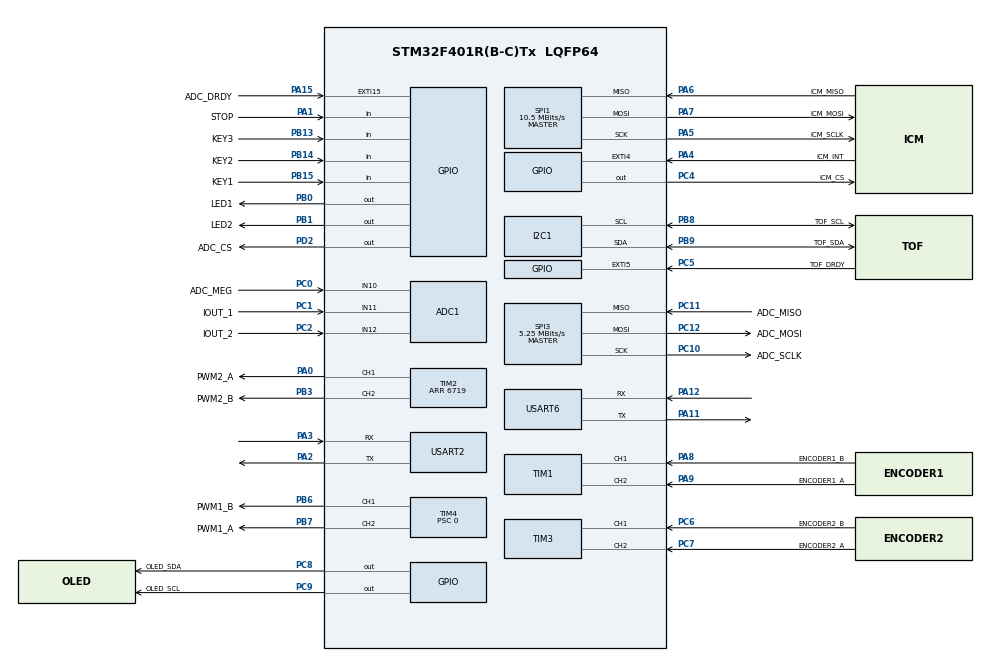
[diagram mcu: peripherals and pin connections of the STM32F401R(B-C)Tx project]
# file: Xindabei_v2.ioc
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ADC1.Channel-0\#ChannelRegularConversion=ADC_CHANNEL_10
ADC1.Channel-3\#ChannelInjectedConversion=ADC_CHANNEL_11
ADC1.Channel-4\#ChannelInjectedConversion=ADC_CHANNEL_12
ADC1.ExternalTrigConv=ADC_SOFTWARE_START
ADC1.ExternalTrigInjecConv=ADC_INJECTED_SOFTWARE_START
ADC1.InjNumberOfConversion=2
ADC1.InjectedOffset-3\#ChannelInjectedConversion=0
ADC1.InjectedOffset-4\#ChannelInjectedConversion=0
ADC1.InjectedRank-3\#ChannelInjectedConversion=1
ADC1.InjectedRank-4\#ChannelInjectedConversion=2
ADC1.NbrOfConversion=1
ADC1.NbrOfConversionFlag=1
ADC1.Rank-0\#ChannelRegularConversion=1
ADC1.SamplingTime-0\#ChannelRegularConversion=ADC_SAMPLETIME_480CYCLES
ADC1.SamplingTime-3\#ChannelInjectedConversion=ADC_SAMPLETIME_56CYCLES
ADC1.SamplingTime-4\#ChannelInjectedConversion=ADC_SAMPLETIME_56CYCLES
ADC1.master=1
Dma.ADC1.3.Direction=DMA_PERIPH_TO_MEMORY
Dma.ADC1.3.FIFOMode=DMA_FIFOMODE_DISABLE
Dma.ADC1.3.Instance=DMA2_Stream0
Dma.ADC1.3.MemDataAlignment=DMA_MDATAALIGN_HALFWORD
Dma.ADC1.3.MemInc=DMA_MINC_ENABLE
Dma.ADC1.3.Mode=DMA_CIRCULAR
Dma.ADC1.3.PeriphDataAlignment=DMA_PDATAALIGN_HALFWORD
Dma.ADC1.3.PeriphInc=DMA_PINC_DISABLE
Dma.ADC1.3.Priority=DMA_PRIORITY_LOW
Dma.Request0=USART2_RX
Dma.Request1=USART2_TX
Dma.Request2=SPI1_TX
Dma.Request3=ADC1
Dma.Request4=USART6_RX
Dma.Request5=USART6_TX
Dma.SPI1_TX.2.Direction=DMA_MEMORY_TO_PERIPH
Dma.SPI1_TX.2.FIFOMode=DMA_FIFOMODE_DISABLE
Dma.SPI1_TX.2.Instance=DMA2_Stream3
Dma.SPI1_TX.2.MemDataAlignment=DMA_MDATAALIGN_BYTE
Dma.SPI1_TX.2.MemInc=DMA_MINC_ENABLE
Dma.SPI1_TX.2.Mode=DMA_NORMAL
Dma.SPI1_TX.2.PeriphDataAlignment=DMA_PDATAALIGN_BYTE
Dma.SPI1_TX.2.PeriphInc=DMA_PINC_DISABLE
Dma.SPI1_TX.2.Priority=DMA_PRIORITY_LOW
Dma.USART2_RX.0.Direction=DMA_PERIPH_TO_MEMORY
Dma.USART2_RX.0.FIFOMode=DMA_FIFOMODE_DISABLE
Dma.USART2_RX.0.Instance=DMA1_Stream5
Dma.USART2_RX.0.MemDataAlignment=DMA_MDATAALIGN_BYTE
Dma.USART2_RX.0.MemInc=DMA_MINC_ENABLE
Dma.USART2_RX.0.Mode=DMA_NORMAL
Dma.USART2_RX.0.PeriphDataAlignment=DMA_PDATAALIGN_BYTE
Dma.USART2_RX.0.PeriphInc=DMA_PINC_DISABLE
Dma.USART2_RX.0.Priority=DMA_PRIORITY_LOW
Dma.USART2_TX.1.Direction=DMA_MEMORY_TO_PERIPH
Dma.USART2_TX.1.FIFOMode=DMA_FIFOMODE_DISABLE
Dma.USART2_TX.1.Instance=DMA1_Stream6
Dma.USART2_TX.1.MemDataAlignment=DMA_MDATAALIGN_BYTE
Dma.USART2_TX.1.MemInc=DMA_MINC_ENABLE
Dma.USART2_TX.1.Mode=DMA_NORMAL
Dma.USART2_TX.1.PeriphDataAlignment=DMA_PDATAALIGN_BYTE
Dma.USART2_TX.1.PeriphInc=DMA_PINC_DISABLE
Dma.USART2_TX.1.Priority=DMA_PRIORITY_LOW
Dma.USART6_RX.4.Direction=DMA_PERIPH_TO_MEMORY
Dma.USART6_RX.4.FIFOMode=DMA_FIFOMODE_DISABLE
Dma.USART6_RX.4.Instance=DMA2_Stream1
Dma.USART6_RX.4.MemDataAlignment=DMA_MDATAALIGN_BYTE
Dma.USART6_RX.4.MemInc=DMA_MINC_ENABLE
Dma.USART6_RX.4.Mode=DMA_NORMAL
Dma.USART6_RX.4.PeriphDataAlignment=DMA_PDATAALIGN_BYTE
Dma.USART6_RX.4.PeriphInc=DMA_PINC_DISABLE
Dma.USART6_RX.4.Priority=DMA_PRIORITY_LOW
Dma.USART6_TX.5.Direction=DMA_MEMORY_TO_PERIPH
Dma.USART6_TX.5.FIFOMode=DMA_FIFOMODE_DISABLE
Dma.USART6_TX.5.Instance=DMA2_Stream6
Dma.USART6_TX.5.MemDataAlignment=DMA_MDATAALIGN_BYTE
Dma.USART6_TX.5.MemInc=DMA_MINC_ENABLE
Dma.USART6_TX.5.Mode=DMA_NORMAL
Dma.USART6_TX.5.PeriphDataAlignment=DMA_PDATAALIGN_BYTE
Dma.USART6_TX.5.PeriphInc=DMA_PINC_DISABLE
Dma.USART6_TX.5.Priority=DMA_PRIORITY_LOW
FREERTOS.Queues01=uartQueue,128,uint16_t,0,Dynamic,NULL,NULL
FREERTOS.Tasks01=defaultTask,21,386,StartDefaultTask,Default,NULL,Dynamic,NULL,NULL;ToFCapture,15,512,TofTask,Default,NULL,Dynamic,NULL,NULL;UartTask,8,512,UartTaskFunc,Default,NULL,Dynamic,NULL,NULL;MotorSpeedTask,48,256,MotorSpeedTaskFunc,Default,NULL,Dynamic,NULL,NULL;AdcCapture,48,512,AdcCaptureFunc,Default,NULL,Dynamic,NULL,NULL;CarControlTask,32,256,CarControlTaskFunc,Default,NULL,Dynamic,NULL,NULL;GyroTask,25,256,GyroTaskFunc,Default,NULL,Dynamic,NULL,NULL;TrackTask,28,256,TrackTaskFunc,Default,NULL,Dynamic,NULL,NULL
FREERTOS.configENABLE_FPU=1
I2C1.I2C_Mode=I2C_Fast
Mcu.Family=STM32F4
Mcu.Name=STM32F401R(B-C)Tx
Mcu.Package=LQFP64
NVIC.DMA1_Stream5_IRQn=true\:5\:0\:false\:false\:true\:true\:false\:true\:true
NVIC.DMA1_Stream6_IRQn=true\:5\:0\:false\:false\:true\:true\:false\:true\:true
NVIC.DMA2_Stream0_IRQn=true\:5\:0\:false\:false\:true\:false\:false\:true\:true
NVIC.DMA2_Stream1_IRQn=true\:5\:0\:false\:false\:true\:true\:false\:true\:true
NVIC.DMA2_Stream3_IRQn=true\:5\:0\:false\:false\:true\:true\:false\:true\:true
NVIC.DMA2_Stream6_IRQn=true\:5\:0\:false\:false\:true\:true\:false\:true\:true
NVIC.EXTI15_10_IRQn=true\:5\:0\:false\:false\:true\:true\:true\:true\:true
NVIC.EXTI4_IRQn=true\:5\:0\:false\:false\:true\:true\:true\:true\:true
NVIC.EXTI9_5_IRQn=true\:5\:0\:false\:false\:true\:true\:true\:true\:true
NVIC.PriorityGroup=NVIC_PRIORITYGROUP_4
NVIC.TIM1_TRG_COM_TIM11_IRQn=true\:15\:0\:false\:false\:true\:false\:false\:true\:true
NVIC.TimeBase=TIM1_TRG_COM_TIM11_IRQn
NVIC.TimeBaseIP=TIM11
NVIC.USART2_IRQn=true\:5\:0\:false\:false\:true\:true\:true\:true\:true
NVIC.USART6_IRQn=true\:5\:0\:false\:false\:true\:true\:true\:true\:true
PA0-WKUP.GPIO_Label=PWM2_A
PA0-WKUP.Signal=S_TIM2_CH1_ETR
PA1.GPIO_Label=STOP
PA1.GPIO_PuPd=GPIO_PULLUP
PA1.Signal=GPIO_Input
PA11.Mode=Asynchronous
PA11.Signal=USART6_TX
PA12.Mode=Asynchronous
PA12.Signal=USART6_RX
PA13.Mode=Serial_Wire
PA13.Signal=SYS_JTMS-SWDIO
PA14.Mode=Serial_Wire
PA14.Signal=SYS_JTCK-SWCLK
PA15.GPIO_Label=ADC_DRDY
PA15.GPIO_ModeDefaultEXTI=GPIO_MODE_IT_FALLING
PA15.GPIO_PuPd=GPIO_PULLUP
PA15.Signal=GPXTI15
PA2.GPIO_PuPd=GPIO_PULLUP
PA2.Mode=Asynchronous
PA2.Signal=USART2_TX
PA3.GPIO_PuPd=GPIO_PULLUP
PA3.Mode=Asynchronous
PA3.Signal=USART2_RX
PA4.GPIO_Label=ICM_INT
PA4.GPIO_PuPd=GPIO_PULLUP
PA4.Signal=GPXTI4
PA5.GPIO_Label=ICM_SCLK
PA5.Mode=Full_Duplex_Master
PA5.Signal=SPI1_SCK
PA6.GPIO_Label=ICM_MISO
PA6.Mode=Full_Duplex_Master
PA6.Signal=SPI1_MISO
PA7.GPIO_Label=ICM_MOSI
PA7.Mode=Full_Duplex_Master
PA7.Signal=SPI1_MOSI
PA8.GPIO_Label=ENCODER1_B
PA8.GPIO_PuPd=GPIO_PULLUP
PA8.Signal=S_TIM1_CH1
PA9.GPIO_Label=ENCODER1_A
PA9.GPIO_ModeDefaultPP=GPIO_MODE_AF_PP
PA9.GPIO_PuPd=GPIO_PULLUP
PA9.Signal=S_TIM1_CH2
PB0.GPIO_Label=LED1
PB0.Signal=GPIO_Output
PB1.GPIO_Label=LED2
PB1.Signal=GPIO_Output
PB13.GPIO_Label=KEY3
PB13.GPIO_PuPd=GPIO_PULLUP
PB13.Signal=GPIO_Input
PB14.GPIO_Label=KEY2
PB14.GPIO_PuPd=GPIO_PULLUP
PB14.Signal=GPIO_Input
PB15.GPIO_Label=KEY1
PB15.GPIO_PuPd=GPIO_PULLUP
PB15.Signal=GPIO_Input
PB3.GPIO_Label=PWM2_B
PB3.Signal=S_TIM2_CH2
PB6.GPIO_Label=PWM1_B
PB6.Signal=S_TIM4_CH1
PB7.GPIO_Label=PWM1_A
PB7.Signal=S_TIM4_CH2
PB8.GPIO_Label=TOF_SCL
PB8.Mode=I2C
PB8.Signal=I2C1_SCL
PB9.GPIO_Label=TOF_SDA
PB9.Mode=I2C
PB9.Signal=I2C1_SDA
PC0.GPIO_Label=ADC_MEG
PC0.Signal=ADCx_IN10
PC1.GPIO_Label=IOUT_1
PC1.Signal=ADCx_IN11
PC10.GPIO_Label=ADC_SCLK
PC10.Mode=Full_Duplex_Master
PC10.Signal=SPI3_SCK
PC11.GPIO_Label=ADC_MISO
PC11.Mode=Full_Duplex_Master
PC11.Signal=SPI3_MISO
PC12.GPIO_Label=ADC_MOSI
PC12.Mode=Full_Duplex_Master
PC12.Signal=SPI3_MOSI
PC2.GPIO_Label=IOUT_2
PC2.Signal=ADCx_IN12
PC4.GPIO_Label=ICM_CS
PC4.GPIO_PuPd=GPIO_NOPULL
PC4.GPIO_Speed=GPIO_SPEED_FREQ_VERY_HIGH
PC4.PinState=GPIO_PIN_SET
PC4.Signal=GPIO_Output
PC5.GPIO_Label=TOF_DRDY
PC5.GPIO_ModeDefaultEXTI=GPIO_MODE_IT_FALLING
PC5.Signal=GPXTI5
PC6.GPIO_Label=ENCODER2_B
PC6.GPIO_PuPd=GPIO_PULLUP
PC6.Signal=S_TIM3_CH1
PC7.GPIO_Label=ENCODER2_A
PC7.GPIO_PuPd=GPIO_PULLUP
PC7.Signal=S_TIM3_CH2
PC8.GPIO_Label=OLED_SDA
PC8.GPIO_ModeDefaultOutputPP=GPIO_MODE_OUTPUT_PP
PC8.GPIO_PuPd=GPIO_NOPULL
PC8.GPIO_Speed=GPIO_SPEED_FREQ_HIGH
PC8.PinState=GPIO_PIN_SET
PC8.Signal=GPIO_Output
PC9.GPIO_Label=OLED_SCL
PC9.GPIO_ModeDefaultOutputPP=GPIO_MODE_OUTPUT_PP
PC9.GPIO_PuPd=GPIO_NOPULL
PC9.GPIO_Speed=GPIO_SPEED_FREQ_HIGH
PC9.PinState=GPIO_PIN_SET
PC9.Signal=GPIO_Output
PD2.GPIO_Label=ADC_CS
PD2.GPIO_Speed=GPIO_SPEED_FREQ_VERY_HIGH
PD2.Signal=GPIO_Output
PH0\ -\ OSC_IN.Mode=HSE-External-Oscillator
PH0\ -\ OSC_IN.Signal=RCC_OSC_IN
PH1\ -\ OSC_OUT.Mode=HSE-External-Oscillator
PH1\ -\ OSC_OUT.Signal=RCC_OSC_OUT
ProjectManager.HeapSize=0x400
ProjectManager.StackSize=0x600
ProjectManager.TargetToolchain=CMake
RCC.48MHZClocksFreq_Value=42000000
RCC.AHBFreq_Value=84000000
RCC.APB1CLKDivider=RCC_HCLK_DIV2
RCC.APB1Freq_Value=42000000
RCC.APB1TimFreq_Value=84000000
RCC.APB2Freq_Value=84000000
RCC.APB2TimFreq_Value=84000000
RCC.CortexFreq_Value=84000000
RCC.HCLKFreq_Value=84000000
RCC.HSE_VALUE=16000000
RCC.HSI_VALUE=16000000
RCC.LSE_VALUE=32768
RCC.PLLM=8
RCC.PLLN=84
RCC.PLLSourceVirtual=RCC_PLLSOURCE_HSE
RCC.SYSCLKFreq_VALUE=84000000
RCC.SYSCLKSource=RCC_SYSCLKSOURCE_PLLCLK
RCC.VCOOutputFreq_Value=168000000
SH.ADCx_IN10.0=ADC1_IN10,IN10
SH.ADCx_IN11.0=ADC1_IN11,IN11
SH.ADCx_IN12.0=ADC1_IN12,IN12
SH.S_TIM1_CH1.0=TIM1_CH1,Encoder_Interface
SH.S_TIM1_CH2.0=TIM1_CH2,Encoder_Interface
SH.S_TIM2_CH1_ETR.0=TIM2_CH1,PWM Generation1 CH1
SH.S_TIM2_CH2.0=TIM2_CH2,PWM Generation2 CH2
SH.S_TIM3_CH1.0=TIM3_CH1,Encoder_Interface
SH.S_TIM3_CH2.0=TIM3_CH2,Encoder_Interface
SH.S_TIM4_CH1.0=TIM4_CH1,PWM Generation1 CH1
SH.S_TIM4_CH2.0=TIM4_CH2,PWM Generation2 CH2
SPI1.BaudRatePrescaler=SPI_BAUDRATEPRESCALER_8
SPI1.CLKPhase=SPI_PHASE_2EDGE
SPI1.CLKPolarity=SPI_POLARITY_HIGH
SPI1.CalculateBaudRate=10.5 MBits/s
SPI1.Direction=SPI_DIRECTION_2LINES
SPI1.Mode=SPI_MODE_MASTER
SPI1.VirtualType=VM_MASTER
SPI3.BaudRatePrescaler=SPI_BAUDRATEPRESCALER_8
SPI3.CLKPhase=SPI_PHASE_2EDGE
SPI3.CalculateBaudRate=5.25 MBits/s
SPI3.Direction=SPI_DIRECTION_2LINES
SPI3.Mode=SPI_MODE_MASTER
SPI3.VirtualType=VM_MASTER
TIM1.EncoderMode=TIM_ENCODERMODE_TI12
TIM1.IC1Filter=5
TIM1.IC1Polarity=TIM_ICPOLARITY_FALLING
TIM1.IC2Filter=5
TIM1.IC2Polarity=TIM_ICPOLARITY_FALLING
TIM2.Channel-PWM\ Generation1\ CH1=TIM_CHANNEL_1
TIM2.Channel-PWM\ Generation2\ CH2=TIM_CHANNEL_2
TIM2.Period=6719
TIM3.EncoderMode=TIM_ENCODERMODE_TI12
TIM3.IC1Filter=5
TIM3.IC1Polarity=TIM_ICPOLARITY_RISING
TIM3.IC2Filter=5
TIM3.IC2Polarity=TIM_ICPOLARITY_RISING
TIM4.AutoReloadPreload=TIM_AUTORELOAD_PRELOAD_ENABLE
TIM4.Channel-PWM\ Generation1\ CH1=TIM_CHANNEL_1
TIM4.Channel-PWM\ Generation2\ CH2=TIM_CHANNEL_2
TIM4.ClockDivision=TIM_CLOCKDIVISION_DIV1
TIM4.Period=6719
TIM4.Prescaler=0
TIM4.Pulse-PWM\ Generation1\ CH1=0
TIM5.Period=5000
TIM5.Prescaler=8
TIM5.TIM_MasterOutputTrigger=TIM_TRGO_UPDATE
TIM9.AutoReloadPreload=TIM_AUTORELOAD_PRELOAD_ENABLE
TIM9.ClockDivision=TIM_CLOCKDIVISION_DIV1
TIM9.Period=9550
TIM9.Prescaler=8
USART2.VirtualMode=VM_ASYNC
USART6.VirtualMode=VM_ASYNC
VP_FREERTOS_VS_CMSIS_V2.Mode=CMSIS_V2
VP_SYS_VS_tim11.Mode=TIM11
VP_TIM5_VS_ClockSourceINT.Mode=Internal
VP_TIM9_VS_ClockSourceINT.Mode=Internal
board=custom

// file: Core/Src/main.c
/* USER CODE BEGIN Header */
/**
 ******************************************************************************
 * @file           : main.c
 * @brief          : Main program body
 ******************************************************************************
 * @attention
 *
 * Copyright (c) 2025 STMicroelectronics.
 * All rights reserved.
 *
 * This software is licensed under terms that can be found in the LICENSE file
 * in the root directory of this software component.
 * If no LICENSE file comes with this software, it is provided AS-IS.
 *
 ******************************************************************************
 */
/*
                  _ooOoo_
                 o8888888o
                 88" . "88
                 (| -_- |)
                 O\ = /O
              ____/`---'\____
            .' \\| |// `
           / \\||| : |||// \
          / _||||| -:- |||||- \
          | | \\\ - /// | |
          | \_| ''\---/'' | |
          \ .-\__ `-` ___/-. /
        ___`. .' /--.--\ `. . __
     ."" '< `.___\_<|>_/___.' >'""
    | | : `- \`.;`\ _ /`;.`/ - ` : | |
    \ \ `-. \_ __\ /__ _/ .-` / /
======`-.____`-.___\_____/___.-`____.-'======
                  `=---='
^^^^^^^^^^^^^^^^^^^^^^^^^^^^^^^^^^^^^^^^^^^^^
           佛祖保佑 永无BUG
*/
/* USER CODE END Header */
#include "main.h"
#include "cmsis_os.h"
#include "adc.h"
#include "dma.h"
#include "i2c.h"
#include "spi.h"
#include "tim.h"
#include "usart.h"
#include "gpio.h"

/* USER CODE BEGIN Includes */
#include "motor.h"
/* USER CODE END Includes */

void SystemClock_Config(void);
void MX_FREERTOS_Init(void);

int main(void)
{

  /* MCU Configuration--------------------------------------------------------*/

  /* Reset of all peripherals, Initializes the Flash interface and the Systick. */
  HAL_Init();

  /* Configure the system clock */
  SystemClock_Config();

  /* Initialize all configured peripherals */
  MX_GPIO_Init();
  MX_DMA_Init();
  MX_TIM1_Init();
  MX_USART2_UART_Init();
  MX_SPI1_Init();
  MX_I2C1_Init();
  MX_ADC1_Init();
  MX_SPI3_Init();
  MX_TIM3_Init();
  MX_TIM4_Init();
  MX_TIM2_Init();
  MX_TIM9_Init();
  MX_TIM5_Init();
  MX_USART6_UART_Init();
  /* USER CODE BEGIN 2 */
  HAL_TIM_Base_Start_IT(&htim9); // 启动电流环定时器

  /* USER CODE END 2 */

  /* Init scheduler */
  osKernelInitialize();  /* Call init function for freertos objects (in cmsis_os2.c) */
  MX_FREERTOS_Init();

  /* Start scheduler */
  osKernelStart();

  /* We should never get here as control is now taken by the scheduler */

  /* Infinite loop */
  while (1) {

    /* USER CODE BEGIN 3 */
    HAL_GPIO_TogglePin(GPIOC, GPIO_PIN_13);
    osDelay(100);
  }
  /* USER CODE END 3 */
}

void SystemClock_Config(void)
{
  RCC_OscInitTypeDef RCC_OscInitStruct = {0};
  RCC_ClkInitTypeDef RCC_ClkInitStruct = {0};

  /** Configure the main internal regulator output voltage
  */
  __HAL_RCC_PWR_CLK_ENABLE();
  __HAL_PWR_VOLTAGESCALING_CONFIG(PWR_REGULATOR_VOLTAGE_SCALE1);  // Scale1 for higher frequency

  /** Initializes the RCC Oscillators according to the specified parameters
  * in the RCC_OscInitTypeDef structure.
  * OVERCLOCK: 96 MHz (official max is 84 MHz)
  * PLL_VCO = HSE / PLLM * PLLN = 16 / 8 * 96 = 192 MHz
  * SYSCLK = PLL_VCO / PLLP = 192 / 2 = 96 MHz
  */
  RCC_OscInitStruct.OscillatorType = RCC_OSCILLATORTYPE_HSE;
  RCC_OscInitStruct.HSEState = RCC_HSE_ON;
  RCC_OscInitStruct.PLL.PLLState = RCC_PLL_ON;
  RCC_OscInitStruct.PLL.PLLSource = RCC_PLLSOURCE_HSE;
  RCC_OscInitStruct.PLL.PLLM = 8;
  RCC_OscInitStruct.PLL.PLLN = 96;   // OVERCLOCK: 84 -> 96
  RCC_OscInitStruct.PLL.PLLP = RCC_PLLP_DIV2;
  RCC_OscInitStruct.PLL.PLLQ = 4;
  if (HAL_RCC_OscConfig(&RCC_OscInitStruct) != HAL_OK)
  {
    Error_Handler();
  }

  /** Initializes the CPU, AHB and APB buses clocks
  */
  RCC_ClkInitStruct.ClockType = RCC_CLOCKTYPE_HCLK|RCC_CLOCKTYPE_SYSCLK
                              |RCC_CLOCKTYPE_PCLK1|RCC_CLOCKTYPE_PCLK2;
  RCC_ClkInitStruct.SYSCLKSource = RCC_SYSCLKSOURCE_PLLCLK;
  RCC_ClkInitStruct.AHBCLKDivider = RCC_SYSCLK_DIV1;
  RCC_ClkInitStruct.APB1CLKDivider = RCC_HCLK_DIV2;
  RCC_ClkInitStruct.APB2CLKDivider = RCC_HCLK_DIV1;

  if (HAL_RCC_ClockConfig(&RCC_ClkInitStruct, FLASH_LATENCY_3) != HAL_OK)  // OVERCLOCK: 2 -> 3
  {
    Error_Handler();
  }
}

void HAL_TIM_PeriodElapsedCallback(TIM_HandleTypeDef *htim)
{
  /* USER CODE BEGIN Callback 0 */
  if (htim->Instance == TIM9) {
    // 电流环定时器
    CurrentLoopTimerHandler();
  }

  /* USER CODE END Callback 0 */
  if (htim->Instance == TIM11)
  {
    HAL_IncTick();
  }
}

void Error_Handler(void)
{
  __disable_irq();
  while (1) {
  }
}
#ifdef USE_FULL_ASSERT
/**
  * @brief  Reports the name of the source file and the source line number
  *         where the assert_param error has occurred.
  * @param  file: pointer to the source file name
  * @param  line: assert_param error line source number
  * @retval None
  */
void assert_failed(uint8_t *file, uint32_t line)
{
  /* USER CODE BEGIN 6 */
  /* User can add his own implementation to report the file name and line
     number, ex: printf("Wrong parameters value: file %s on line %d\r\n", file,
     line) */
  /* USER CODE END 6 */
}
#endif /* USE_FULL_ASSERT */

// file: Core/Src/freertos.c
/* USER CODE BEGIN Header */
/**
 ******************************************************************************
 * File Name          : freertos.c
 * Description        : Code for freertos applications
 ******************************************************************************
 * @attention
 *
 * Copyright (c) 2025 STMicroelectronics.
 * All rights reserved.
 *
 * This software is licensed under terms that can be found in the LICENSE file
 * in the root directory of this software component.
 * If no LICENSE file comes with this software, it is provided AS-IS.
 *
 ******************************************************************************
 */
/* USER CODE END Header */

#include "FreeRTOS.h"
#include "task.h"
#include "main.h"
#include "cmsis_os.h"

/* USER CODE BEGIN Includes */
#include "car_control.h"
#include "common.h"
#include "imu.h"
#include "meg_adc.h"
#include "motor.h"
#include "oled_service.h"
#include "param_server.h"
#include "tim.h"
#include "tof.h"
#include "track.h"
#include "uart_command.h"
#include "usart.h"
#include <stdint.h>
#include <stdio.h>
#include <string.h>

/* USER CODE END Includes */

/* USER CODE BEGIN Variables */
TaskHandle_t ToFMeasureTaskHandle;
TaskHandle_t AdcCaptureTaskHandle;
TaskHandle_t ImuCaptureTaskHandle;

/* USER CODE END Variables */
/* Definitions for defaultTask */
osThreadId_t defaultTaskHandle;
const osThreadAttr_t defaultTask_attributes = {
  .name = "defaultTask",
  .stack_size = 386 * 4,
  .priority = (osPriority_t) osPriorityBelowNormal5,
};
/* Definitions for ToFCapture */
osThreadId_t ToFCaptureHandle;
const osThreadAttr_t ToFCapture_attributes = {
  .name = "ToFCapture",
  .stack_size = 512 * 4,
  .priority = (osPriority_t) osPriorityLow7,
};
/* Definitions for UartTask */
osThreadId_t UartTaskHandle;
const osThreadAttr_t UartTask_attributes = {
  .name = "UartTask",
  .stack_size = 512 * 4,
  .priority = (osPriority_t) osPriorityLow,
};
/* Definitions for MotorSpeedTask */
osThreadId_t MotorSpeedTaskHandle;
const osThreadAttr_t MotorSpeedTask_attributes = {
  .name = "MotorSpeedTask",
  .stack_size = 256 * 4,
  .priority = (osPriority_t) osPriorityRealtime,
};
/* Definitions for AdcCapture */
osThreadId_t AdcCaptureHandle;
const osThreadAttr_t AdcCapture_attributes = {
  .name = "AdcCapture",
  .stack_size = 512 * 4,
  .priority = (osPriority_t) osPriorityRealtime,
};
/* Definitions for CarControlTask */
osThreadId_t CarControlTaskHandle;
const osThreadAttr_t CarControlTask_attributes = {
  .name = "CarControlTask",
  .stack_size = 256 * 4,
  .priority = (osPriority_t) osPriorityAboveNormal,
};
/* Definitions for GyroTask */
osThreadId_t GyroTaskHandle;
const osThreadAttr_t GyroTask_attributes = {
  .name = "GyroTask",
  .stack_size = 256 * 4,
  .priority = (osPriority_t) osPriorityNormal1,
};
/* Definitions for TrackTask */
osThreadId_t TrackTaskHandle;
const osThreadAttr_t TrackTask_attributes = {
  .name = "TrackTask",
  .stack_size = 256 * 4,
  .priority = (osPriority_t) osPriorityNormal4,
};
/* Definitions for uartQueue */
osMessageQueueId_t uartQueueHandle;
const osMessageQueueAttr_t uartQueue_attributes = {
  .name = "uartQueue"
};

/* USER CODE BEGIN FunctionPrototypes */
void ConfigureTimerForRunTimeStats(void);
unsigned long GetRunTimeCounterValue(void);
float CalculateCpuUsage(void);

// Data Source Callbacks
int32_t GetCpuUsageInt(void)
{
    return (int32_t)CalculateCpuUsage();
}

float GetCpuUsageFloat(void)
{
    return CalculateCpuUsage();
}

int32_t GetTofDistance(void)
{
    return TofGetDistance();
}

/* 注册系统监控参数 */
void RegisterSystemParams(void)
{
    static ParamDesc params[] = {
        /* 默认：串口 + OLED 都显示 */
        {.name = "CPU",
         .type = PARAM_TYPE_FLOAT,
         .ops.f.get = GetCpuUsageFloat,
         .read_only = 1,
         .mask = PARAM_MASK_OLED},

        {.name = "TOF",
         .type = PARAM_TYPE_INT,
         .ops.i.get = (ParamGetIntCb)GetTofDistance,
         .read_only = 1,
         .mask = PARAM_MASK_OLED|PARAM_MASK_SERIAL},
    };

    for (int i = 0; i < sizeof(params) / sizeof(params[0]); i++)
    {
        ParamServer_Register(&params[i]);
    }
}
/* USER CODE END FunctionPrototypes */

void StartDefaultTask(void *argument);
void TofTask(void *argument);
void UartTaskFunc(void *argument);
void MotorSpeedTaskFunc(void *argument);
void AdcCaptureFunc(void *argument);
void CarControlTaskFunc(void *argument);
void GyroTaskFunc(void *argument);
void TrackTaskFunc(void *argument);

void MX_FREERTOS_Init(void); /* (MISRA C 2004 rule 8.1) */

void MX_FREERTOS_Init(void) {

  /* Create the queue(s) */
  /* creation of uartQueue */
  uartQueueHandle = osMessageQueueNew (128, sizeof(uint16_t), &uartQueue_attributes);

  /* Create the thread(s) */
  /* creation of defaultTask */
  defaultTaskHandle = osThreadNew(StartDefaultTask, NULL, &defaultTask_attributes);

  /* creation of ToFCapture */
  ToFCaptureHandle = osThreadNew(TofTask, NULL, &ToFCapture_attributes);

  /* creation of UartTask */
  UartTaskHandle = osThreadNew(UartTaskFunc, NULL, &UartTask_attributes);

  /* creation of MotorSpeedTask */
  MotorSpeedTaskHandle = osThreadNew(MotorSpeedTaskFunc, NULL, &MotorSpeedTask_attributes);

  /* creation of AdcCapture */
  AdcCaptureHandle = osThreadNew(AdcCaptureFunc, NULL, &AdcCapture_attributes);

  /* creation of CarControlTask */
  CarControlTaskHandle = osThreadNew(CarControlTaskFunc, NULL, &CarControlTask_attributes);

  /* creation of GyroTask */
  GyroTaskHandle = osThreadNew(GyroTaskFunc, NULL, &GyroTask_attributes);

  /* creation of TrackTask */
  TrackTaskHandle = osThreadNew(TrackTaskFunc, NULL, &TrackTask_attributes);

}

/* USER CODE BEGIN Header_StartDefaultTask */
/**
 * @brief  Function implementing the defaultTask thread.
 * @param  argument: Not used
 * @retval NoneB
 */
/* USER CODE END Header_StartDefaultTask */
void StartDefaultTask(void *argument)
{
  /* USER CODE BEGIN StartDefaultTask */
    /* Infinite loop */
    OledServiceInit();
    RegisterSystemParams();
    // int i = 1;
    // int j=0;
    for (;;)
    {
        // j++;
        // if (j >= 10)
        // {
        //     i=i>=5?1:i+1;
        //     j=0;
        // }
        // LED_Command(i, true);

        HAL_GPIO_TogglePin(LED2_GPIO_Port, LED2_Pin);

        /* KEY1: Next / Page Down, Long Press: Reset State Machine */
        if (HAL_GPIO_ReadPin(KEY1_GPIO_Port, KEY1_Pin) == GPIO_PIN_RESET)
        {
            osDelay(20); // Debounce
            if (HAL_GPIO_ReadPin(KEY1_GPIO_Port, KEY1_Pin) == GPIO_PIN_RESET)
            {
                uint32_t pressTime = 0;
                bool longPressHandled = false;

                while (HAL_GPIO_ReadPin(KEY1_GPIO_Port, KEY1_Pin) == GPIO_PIN_RESET)
                {
                    osDelay(10);
                    pressTime += 10;
                    if (pressTime > 1000 && !longPressHandled)
                    { // 1s long press - Reset State Machine
                        printf("KEY1 Long Press: Reset\n");
                        TrackSetCommand(TRACK_CMD_RESET);
                        longPressHandled = true;
                    }
                }

                if (!longPressHandled)
                {
                    OledHandleKey(OLED_KEY_NEXT);
                }
            }
        }

        /* KEY2: Start Car (Aggressive Mode - High Speed) */
        if (HAL_GPIO_ReadPin(KEY2_GPIO_Port, KEY2_Pin) == GPIO_PIN_RESET)
        {
            osDelay(20); // Debounce
            if (HAL_GPIO_ReadPin(KEY2_GPIO_Port, KEY2_Pin) == GPIO_PIN_RESET)
            {
                printf("KEY2 Pressed: Start (Aggressive)\n");
                TrackSetCommand(TRACK_CMD_START);
                while (HAL_GPIO_ReadPin(KEY2_GPIO_Port, KEY2_Pin) == GPIO_PIN_RESET)
                    osDelay(10);
            }
        }

        /* KEY3: Start Car (Conservative Mode - Low Speed) / Long Press: Toggle Safety Check */
        if (HAL_GPIO_ReadPin(KEY3_GPIO_Port, KEY3_Pin) == GPIO_PIN_RESET)
        {
            osDelay(20); // Debounce
            if (HAL_GPIO_ReadPin(KEY3_GPIO_Port, KEY3_Pin) == GPIO_PIN_RESET)
            {
                uint32_t pressTime = 0;
                bool longPressHandled = false;

                while (HAL_GPIO_ReadPin(KEY3_GPIO_Port, KEY3_Pin) == GPIO_PIN_RESET)
                {
                    osDelay(10);
                    pressTime += 10;
                    if (pressTime > 1000 && !longPressHandled)
                    { // 1s long press - toggle safety check
                        bool currentSafetyState = TrackIsSafetyCheckEnabled();
                        TrackSetSafetyCheckEnabled(!currentSafetyState);
                        printf("Safety Check %s\n", !currentSafetyState ? "ENABLED" : "DISABLED");
                        longPressHandled = true;
                    }
                }

                if (!longPressHandled)
                {
                    // Short press - start with conservative mode
                    printf("KEY3 Pressed: Start (Conservative)\n");
                    TrackSetCommand(TRACK_CMD_START_CONSERVATIVE);
                }        // // 3. 环岛检测
        // if (m_ringFilter.Update(res.m >= 1.6 || m_ringFilter.count >= 5, 20))
        // {
        //     m_ringFilter.Reset();
        //     return TRACK_STATE_PRE_RING;
        // }
        // return TRACK_STATE_TRACKING;
            }
        }

        // OledServiceUpdate();
        print_handler();
        osDelay(50); // 提高刷新率以响应按键
    }
  /* USER CODE END StartDefaultTask */
}

void TofTask(void *argument)
{
  /* USER CODE BEGIN TofTask */
    ToFMeasureTaskHandle = xTaskGetCurrentTaskHandle();
    TofInit();

    for (;;)
    {
        TofHandler();
    }
  /* USER CODE END TofTask */
}

void UartTaskFunc(void *argument)
{
  /* USER CODE BEGIN UartTaskFunc */
    HAL_UARTEx_ReceiveToIdle_DMA(&huart6, uart_rx_buf, UART_BUF_LEN);
    uint16_t len;
    while (1)
    {
        if (osMessageQueueGet(uartQueueHandle, &len, NULL, osWaitForever) == osOK)
        {
            handle_command(uart_rx_buf, len);
        }
    }
  /* USER CODE END UartTaskFunc */
}

void MotorSpeedTaskFunc(void *argument)
{
  /* USER CODE BEGIN MotorSpeedTaskFunc */
    /* Infinite loop */
    MotorInit();
    TickType_t xLast = xTaskGetTickCount();
    const TickType_t freq = pdMS_TO_TICKS(5); // 200 Hz

    for (;;)
    {
        SpeedLoopHandler();
        vTaskDelayUntil(&xLast, freq);
    }
  /* USER CODE END MotorSpeedTaskFunc */
}

void AdcCaptureFunc(void *argument)
{
  /* USER CODE BEGIN AdcCaptureFunc */
    AdcCaptureTaskHandle = xTaskGetCurrentTaskHandle();
    MegAdcInit();
    /* Infinite loop */
    for (;;)
    {
        MegAdcHandler();
    }
  /* USER CODE END AdcCaptureFunc */
}

void CarControlTaskFunc(void *argument)
{
  /* USER CODE BEGIN CarControlTaskFunc */
    /* Infinite loop */
    CarControlInit();
    TickType_t xLastWakeTime = xTaskGetTickCount();
    const TickType_t xFrequency = pdMS_TO_TICKS(10); // 10ms 周期
    for (;;)
    {
        CarControlHandler();
        vTaskDelayUntil(&xLastWakeTime, xFrequency);
    }
  /* USER CODE END CarControlTaskFunc */
}

void GyroTaskFunc(void *argument)
{
  /* USER CODE BEGIN GyroTaskFunc */
    ImuCaptureTaskHandle = xTaskGetCurrentTaskHandle();
    /* Infinite loop */
    IMUInit();
    for (;;)
    {
        // 等待IMU中断通知
        ulTaskNotifyTake(pdTRUE, portMAX_DELAY);
        // 收到中断后处理IMU数据
        IMUHandler();
    }
  /* USER CODE END GyroTaskFunc */
}

void TrackTaskFunc(void *argument)
{
  /* USER CODE BEGIN TrackTaskFunc */
    /* Infinite loop */
    TrackInit();
    TickType_t xLastWakeTime = xTaskGetTickCount();
    const TickType_t xFrequency = pdMS_TO_TICKS(10); // 10ms 周期
    for (;;)
    {
        TrackHandler();
        vTaskDelayUntil(&xLastWakeTime, xFrequency);
    }
  /* USER CODE END TrackTaskFunc */
}

/* USER CODE BEGIN Application */
void ConfigureTimerForRunTimeStats(void)
{
    CoreDebug->DEMCR |= CoreDebug_DEMCR_TRCENA_Msk;
    DWT->CYCCNT = 0;
    DWT->CTRL |= DWT_CTRL_CYCCNTENA_Msk;
}

unsigned long GetRunTimeCounterValue(void)
{
    return DWT->CYCCNT;
}

float CalculateCpuUsage(void)
{
    static uint32_t ulLastIdleTime = 0;
    static uint32_t ulLastTotalTime = 0;
    static float cpuUsage = 0.0f;

    TaskStatus_t *pxTaskStatusArray;
    volatile UBaseType_t uxArraySize, x;
    uint32_t ulTotalRunTime;

    uxArraySize = uxTaskGetNumberOfTasks();
    pxTaskStatusArray = pvPortMalloc(uxArraySize * sizeof(TaskStatus_t));

    if (pxTaskStatusArray != NULL)
    {
        uxArraySize = uxTaskGetSystemState(pxTaskStatusArray, uxArraySize, &ulTotalRunTime);

        for (x = 0; x < uxArraySize; x++)
        {
            if (pxTaskStatusArray[x].xHandle == xTaskGetIdleTaskHandle())
            {
                uint32_t ulIdleTime = pxTaskStatusArray[x].ulRunTimeCounter;
                uint32_t ulTotalTime = ulTotalRunTime;

                uint32_t ulIdleDelta = ulIdleTime - ulLastIdleTime;
                uint32_t ulTotalDelta = ulTotalTime - ulLastTotalTime;

                if (ulTotalDelta > 0)
                {
                    cpuUsage = 100.0f * (1.0f - ((float)ulIdleDelta / (float)ulTotalDelta));
                }

                ulLastIdleTime = ulIdleTime;
                ulLastTotalTime = ulTotalTime;
                break;
            }
        }
        vPortFree(pxTaskStatusArray);
    }

    return cpuUsage;
}
/* USER CODE END Application */
